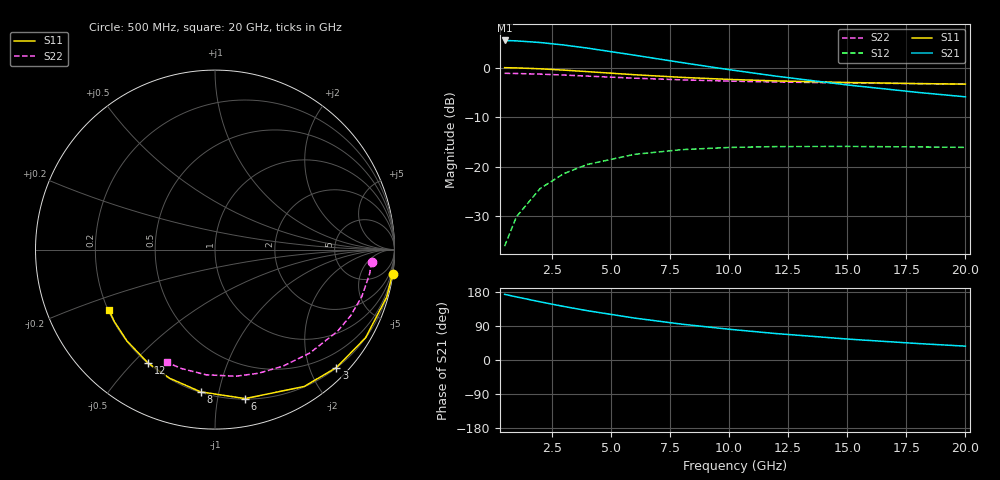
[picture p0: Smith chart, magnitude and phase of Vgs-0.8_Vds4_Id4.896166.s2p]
# Hz S RI R 50
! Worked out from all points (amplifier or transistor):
!   12 points, 500 MHz to 20 GHz, reference 50 ohm
!   highest |S21| = 5.5 dB at 500 MHz (marker M1)
!   |S21| within 3 dB of that: start of sweep to 6.033 GHz
!   unconditionally stable (mu >= 1): 13.81 GHz to end of sweep
!   at 2 GHz: K = 0.12, MSG = 14.7 dB, |S12| = -24.4 dB
!   at 8 GHz: K = 0.51, MSG = 8.8 dB, |S12| = -16.6 dB
!   at 20 GHz: K = 1.68, MAG = 0.3 dB, |S12| = -16.1 dB
!   S11 on the Smith chart (normalised r, x): 500 MHz: 0, -15; 3 GHz: 0.21, -2.45; 6 GHz: 0.20, -1.20; 8 GHz: 0.20, -0.88; 12 GHz: 0.20, -0.55; 20 GHz: 0.20, -0.25
5e8  0.989 -0.1345  -1.865 0.2208  0.00151 0.0157  0.8726 -0.069
1e9  0.9569 -0.2639  -1.809 0.4324  0.00591 0.0307  0.8611 -0.1364
2e9  0.8395 -0.4903  -1.603 0.7972  0.0219 0.056  0.8182 -0.2616
3e9  0.6763 -0.6573  -1.32 1.055  0.0438 0.0728  0.7558 -0.3682
4e9  0.497 -0.7626  -1.014 1.203  0.0673 0.081  0.6826 -0.4551
6e9  0.1681 -0.8301  -0.4702 1.248  0.1081 0.0778  0.5279 -0.5766
8e9  -0.08 -0.7926  -0.0893 1.119  0.1353 0.0616  0.379 -0.6493
1e10  -0.2534 -0.7164  0.1469 0.9415  0.1505 0.0423  0.2417 -0.6891
1.2e10  -0.3736 -0.6313  0.2842 0.7677  0.1577 0.0242  0.1164 -0.7054
1.5e10  -0.4903 -0.5094  0.3804 0.5494  0.1601 0.00184  -0.0491 -0.6976
1.8e10  -0.5607 -0.4012  0.4078 0.3857  0.1576 -0.015  -0.1877 -0.6624
2e10  -0.5915 -0.3365  0.4073 0.3018  0.1548 -0.0238  -0.266 -0.6288
